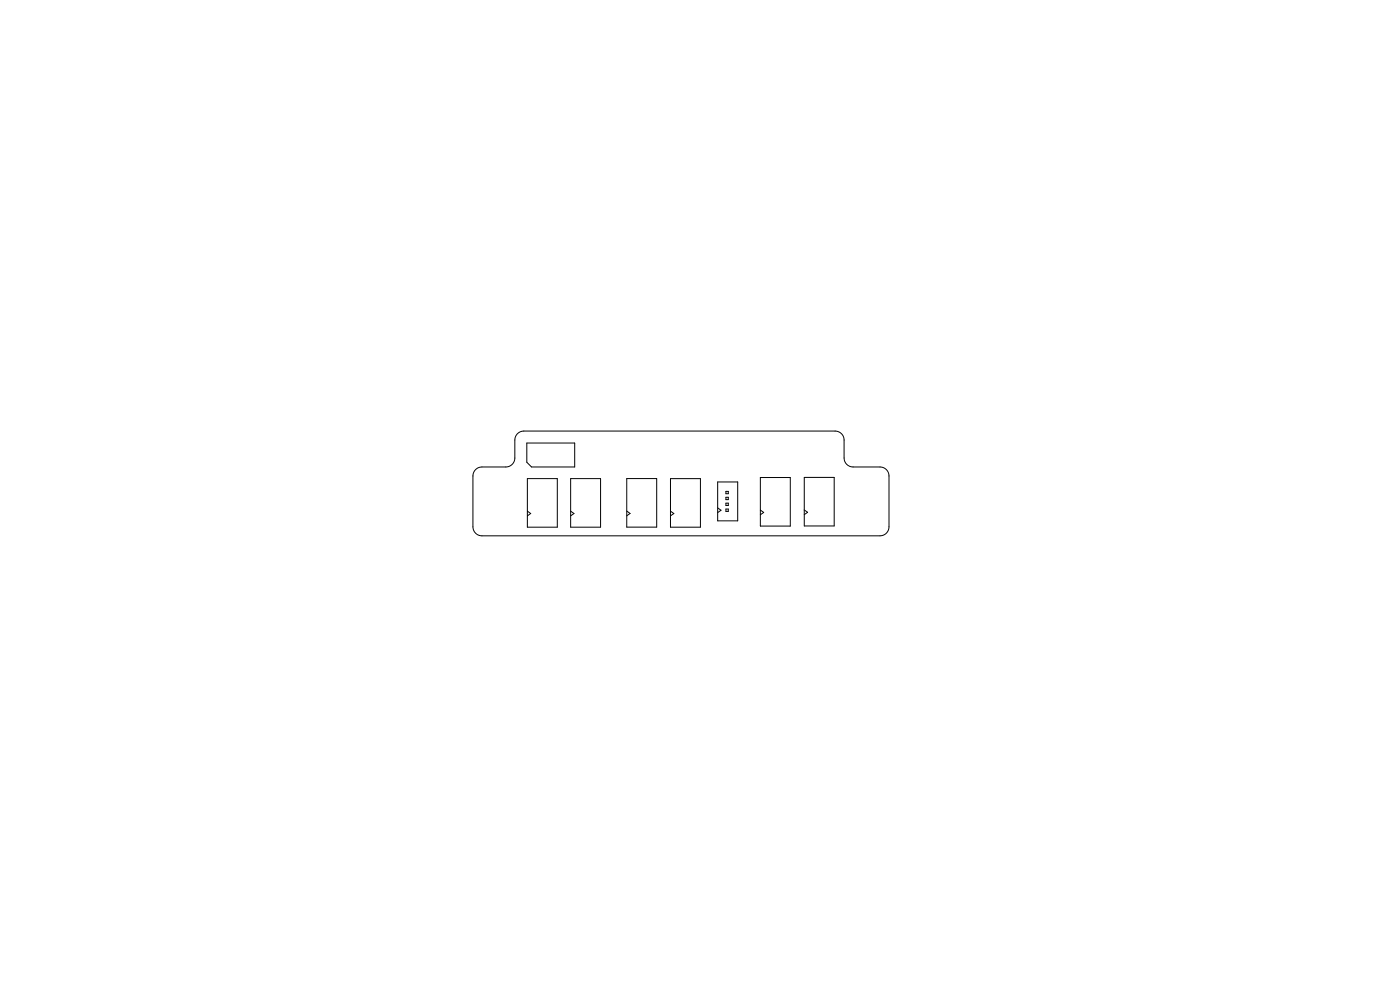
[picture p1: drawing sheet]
<svg xmlns="http://www.w3.org/2000/svg" width="297mm" height="210mm" viewBox="0 0 297 210" stroke-linecap="round" stroke-linejoin="round" font-family="sans-serif">
<g fill="none" stroke="#000" stroke-width=".21">
<path d="M100.8 99.7l.7-.5 .5-.1h5.3a1.9 1.9 0 0 0 1.9-1.9v-3.9a1.9 1.9 0 0 1 1.9-1.9h66.1a1.9 1.9 0 0 1 1.9 1.9v3.9a1.9 1.9 0 0 0 1.9 1.9h5.7a1.9 1.9 0 0 1 1.9 1.9v10.8a1.9 1.9 0 0 1-1.9 1.9h-84.5a1.9 1.9 0 0 1-1.9-1.9v-10.8l.1-.6zM111.8 94h10.1v5.1h-9.1l-1-1zM111.9 101.5h6.3v10.3h-6.3zM111.9 108.4l.7 .5-.7 .5M121.1 101.5h6.3v10.3h-6.3zM121.1 108.4l.7 .5-.7 .5M133 101.5h6.3v10.3h-6.3zM133 108.4l.7 .5-.7 .5M142.2 108.4l.7 .5-.7 .5M142.2 101.5h6.4v10.3h-6.4zM152.3 107.7l.7 .5-.7 .5M152.3 102.2h4.2v8.3h-4.2z"/>
<path d="M154 108h.5v.5h-.5zM154 104.2h.5v.5h-.5zM154 105.5h.5v.5h-.5zM154 106.7h.5v.5h-.5zM161.3 101.3h6.4v10.3h-6.4zM161.3 108.2l.7 .5-.7 .5M170.6 108.2l.7 .5-.7 .5M170.6 101.3h6.4v10.3h-6.4z"/>
</g>
</svg>
